# Generated by FakeRAM 2.0 (routing-friendly)
VERSION 5.7 ;
BUSBITCHARS "[]" ;
PROPERTYDEFINITIONS
  MACRO width INTEGER ;
  MACRO depth INTEGER ;
  MACRO banks INTEGER ;
END PROPERTYDEFINITIONS
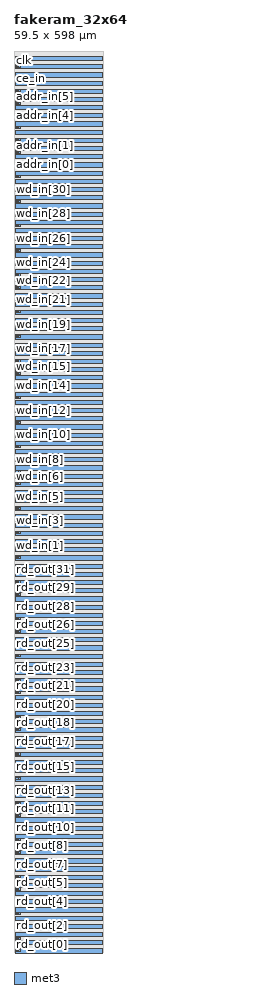
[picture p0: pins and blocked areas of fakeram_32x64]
MACRO fakeram_32x64
  PROPERTY width 32 ;
  PROPERTY depth 64 ;
  PROPERTY banks 1 ;
  FOREIGN fakeram_32x64 0 0 ;
  SYMMETRY X Y R90 ;
  SIZE 59.500 BY 598.000 ;
  CLASS BLOCK ;
  PIN rd_out[0]
    DIRECTION OUTPUT ;
    USE SIGNAL ;
    PORT
      LAYER met3 ;
      RECT 1.000 0.680 3.000 1.380 ;
    END
    PORT
      LAYER met3 ;
      RECT 1.000 0.330 4.000 1.730 ;
    END
  END rd_out[0]
  PIN rd_out[1]
    DIRECTION OUTPUT ;
    USE SIGNAL ;
    PORT
      LAYER met3 ;
      RECT 1.000 8.840 3.000 9.540 ;
    END
    PORT
      LAYER met3 ;
      RECT 1.000 8.490 4.000 9.890 ;
    END
  END rd_out[1]
  PIN rd_out[2]
    DIRECTION OUTPUT ;
    USE SIGNAL ;
    PORT
      LAYER met3 ;
      RECT 1.000 17.000 3.000 17.700 ;
    END
    PORT
      LAYER met3 ;
      RECT 1.000 16.650 4.000 18.050 ;
    END
  END rd_out[2]
  PIN rd_out[3]
    DIRECTION OUTPUT ;
    USE SIGNAL ;
    PORT
      LAYER met3 ;
      RECT 1.000 25.160 3.000 25.860 ;
    END
    PORT
      LAYER met3 ;
      RECT 1.000 24.810 4.000 26.210 ;
    END
  END rd_out[3]
  PIN rd_out[4]
    DIRECTION OUTPUT ;
    USE SIGNAL ;
    PORT
      LAYER met3 ;
      RECT 1.000 33.320 3.000 34.020 ;
    END
    PORT
      LAYER met3 ;
      RECT 1.000 32.970 4.000 34.370 ;
    END
  END rd_out[4]
  PIN rd_out[5]
    DIRECTION OUTPUT ;
    USE SIGNAL ;
    PORT
      LAYER met3 ;
      RECT 1.000 41.480 3.000 42.180 ;
    END
    PORT
      LAYER met3 ;
      RECT 1.000 41.130 4.000 42.530 ;
    END
  END rd_out[5]
  PIN rd_out[6]
    DIRECTION OUTPUT ;
    USE SIGNAL ;
    PORT
      LAYER met3 ;
      RECT 1.000 49.640 3.000 50.340 ;
    END
    PORT
      LAYER met3 ;
      RECT 1.000 49.290 4.000 50.690 ;
    END
  END rd_out[6]
  PIN rd_out[7]
    DIRECTION OUTPUT ;
    USE SIGNAL ;
    PORT
      LAYER met3 ;
      RECT 1.000 57.800 3.000 58.500 ;
    END
    PORT
      LAYER met3 ;
      RECT 1.000 57.450 4.000 58.850 ;
    END
  END rd_out[7]
  PIN rd_out[8]
    DIRECTION OUTPUT ;
    USE SIGNAL ;
    PORT
      LAYER met3 ;
      RECT 1.000 65.960 3.000 66.660 ;
    END
    PORT
      LAYER met3 ;
      RECT 1.000 65.610 4.000 67.010 ;
    END
  END rd_out[8]
  PIN rd_out[9]
    DIRECTION OUTPUT ;
    USE SIGNAL ;
    PORT
      LAYER met3 ;
      RECT 1.000 74.120 3.000 74.820 ;
    END
    PORT
      LAYER met3 ;
      RECT 1.000 73.770 4.000 75.170 ;
    END
  END rd_out[9]
  PIN rd_out[10]
    DIRECTION OUTPUT ;
    USE SIGNAL ;
    PORT
      LAYER met3 ;
      RECT 1.000 82.280 3.000 82.980 ;
    END
    PORT
      LAYER met3 ;
      RECT 1.000 81.930 4.000 83.330 ;
    END
  END rd_out[10]
  PIN rd_out[11]
    DIRECTION OUTPUT ;
    USE SIGNAL ;
    PORT
      LAYER met3 ;
      RECT 1.000 90.440 3.000 91.140 ;
    END
    PORT
      LAYER met3 ;
      RECT 1.000 90.090 4.000 91.490 ;
    END
  END rd_out[11]
  PIN rd_out[12]
    DIRECTION OUTPUT ;
    USE SIGNAL ;
    PORT
      LAYER met3 ;
      RECT 1.000 98.600 3.000 99.300 ;
    END
    PORT
      LAYER met3 ;
      RECT 1.000 98.250 4.000 99.650 ;
    END
  END rd_out[12]
  PIN rd_out[13]
    DIRECTION OUTPUT ;
    USE SIGNAL ;
    PORT
      LAYER met3 ;
      RECT 1.000 106.760 3.000 107.460 ;
    END
    PORT
      LAYER met3 ;
      RECT 1.000 106.410 4.000 107.810 ;
    END
  END rd_out[13]
  PIN rd_out[14]
    DIRECTION OUTPUT ;
    USE SIGNAL ;
    PORT
      LAYER met3 ;
      RECT 1.000 114.920 3.000 115.620 ;
    END
    PORT
      LAYER met3 ;
      RECT 1.000 114.570 4.000 115.970 ;
    END
  END rd_out[14]
  PIN rd_out[15]
    DIRECTION OUTPUT ;
    USE SIGNAL ;
    PORT
      LAYER met3 ;
      RECT 1.000 123.080 3.000 123.780 ;
    END
    PORT
      LAYER met3 ;
      RECT 1.000 122.730 4.000 124.130 ;
    END
  END rd_out[15]
  PIN rd_out[16]
    DIRECTION OUTPUT ;
    USE SIGNAL ;
    PORT
      LAYER met3 ;
      RECT 1.000 131.240 3.000 131.940 ;
    END
    PORT
      LAYER met3 ;
      RECT 1.000 130.890 4.000 132.290 ;
    END
  END rd_out[16]
  PIN rd_out[17]
    DIRECTION OUTPUT ;
    USE SIGNAL ;
    PORT
      LAYER met3 ;
      RECT 1.000 139.400 3.000 140.100 ;
    END
    PORT
      LAYER met3 ;
      RECT 1.000 139.050 4.000 140.450 ;
    END
  END rd_out[17]
  PIN rd_out[18]
    DIRECTION OUTPUT ;
    USE SIGNAL ;
    PORT
      LAYER met3 ;
      RECT 1.000 147.560 3.000 148.260 ;
    END
    PORT
      LAYER met3 ;
      RECT 1.000 147.210 4.000 148.610 ;
    END
  END rd_out[18]
  PIN rd_out[19]
    DIRECTION OUTPUT ;
    USE SIGNAL ;
    PORT
      LAYER met3 ;
      RECT 1.000 155.720 3.000 156.420 ;
    END
    PORT
      LAYER met3 ;
      RECT 1.000 155.370 4.000 156.770 ;
    END
  END rd_out[19]
  PIN rd_out[20]
    DIRECTION OUTPUT ;
    USE SIGNAL ;
    PORT
      LAYER met3 ;
      RECT 1.000 163.880 3.000 164.580 ;
    END
    PORT
      LAYER met3 ;
      RECT 1.000 163.530 4.000 164.930 ;
    END
  END rd_out[20]
  PIN rd_out[21]
    DIRECTION OUTPUT ;
    USE SIGNAL ;
    PORT
      LAYER met3 ;
      RECT 1.000 172.040 3.000 172.740 ;
    END
    PORT
      LAYER met3 ;
      RECT 1.000 171.690 4.000 173.090 ;
    END
  END rd_out[21]
  PIN rd_out[22]
    DIRECTION OUTPUT ;
    USE SIGNAL ;
    PORT
      LAYER met3 ;
      RECT 1.000 180.200 3.000 180.900 ;
    END
    PORT
      LAYER met3 ;
      RECT 1.000 179.850 4.000 181.250 ;
    END
  END rd_out[22]
  PIN rd_out[23]
    DIRECTION OUTPUT ;
    USE SIGNAL ;
    PORT
      LAYER met3 ;
      RECT 1.000 188.360 3.000 189.060 ;
    END
    PORT
      LAYER met3 ;
      RECT 1.000 188.010 4.000 189.410 ;
    END
  END rd_out[23]
  PIN rd_out[24]
    DIRECTION OUTPUT ;
    USE SIGNAL ;
    PORT
      LAYER met3 ;
      RECT 1.000 196.520 3.000 197.220 ;
    END
    PORT
      LAYER met3 ;
      RECT 1.000 196.170 4.000 197.570 ;
    END
  END rd_out[24]
  PIN rd_out[25]
    DIRECTION OUTPUT ;
    USE SIGNAL ;
    PORT
      LAYER met3 ;
      RECT 1.000 204.680 3.000 205.380 ;
    END
    PORT
      LAYER met3 ;
      RECT 1.000 204.330 4.000 205.730 ;
    END
  END rd_out[25]
  PIN rd_out[26]
    DIRECTION OUTPUT ;
    USE SIGNAL ;
    PORT
      LAYER met3 ;
      RECT 1.000 212.840 3.000 213.540 ;
    END
    PORT
      LAYER met3 ;
      RECT 1.000 212.490 4.000 213.890 ;
    END
  END rd_out[26]
  PIN rd_out[27]
    DIRECTION OUTPUT ;
    USE SIGNAL ;
    PORT
      LAYER met3 ;
      RECT 1.000 221.000 3.000 221.700 ;
    END
    PORT
      LAYER met3 ;
      RECT 1.000 220.650 4.000 222.050 ;
    END
  END rd_out[27]
  PIN rd_out[28]
    DIRECTION OUTPUT ;
    USE SIGNAL ;
    PORT
      LAYER met3 ;
      RECT 1.000 229.160 3.000 229.860 ;
    END
    PORT
      LAYER met3 ;
      RECT 1.000 228.810 4.000 230.210 ;
    END
  END rd_out[28]
  PIN rd_out[29]
    DIRECTION OUTPUT ;
    USE SIGNAL ;
    PORT
      LAYER met3 ;
      RECT 1.000 237.320 3.000 238.020 ;
    END
    PORT
      LAYER met3 ;
      RECT 1.000 236.970 4.000 238.370 ;
    END
  END rd_out[29]
  PIN rd_out[30]
    DIRECTION OUTPUT ;
    USE SIGNAL ;
    PORT
      LAYER met3 ;
      RECT 1.000 245.480 3.000 246.180 ;
    END
    PORT
      LAYER met3 ;
      RECT 1.000 245.130 4.000 246.530 ;
    END
  END rd_out[30]
  PIN rd_out[31]
    DIRECTION OUTPUT ;
    USE SIGNAL ;
    PORT
      LAYER met3 ;
      RECT 1.000 253.640 3.000 254.340 ;
    END
    PORT
      LAYER met3 ;
      RECT 1.000 253.290 4.000 254.690 ;
    END
  END rd_out[31]
  PIN wd_in[0]
    DIRECTION INPUT ;
    USE SIGNAL ;
    PORT
      LAYER met3 ;
      RECT 1.000 261.800 3.000 262.500 ;
    END
    PORT
      LAYER met3 ;
      RECT 1.000 261.450 4.000 262.850 ;
    END
  END wd_in[0]
  PIN wd_in[1]
    DIRECTION INPUT ;
    USE SIGNAL ;
    PORT
      LAYER met3 ;
      RECT 1.000 269.960 3.000 270.660 ;
    END
    PORT
      LAYER met3 ;
      RECT 1.000 269.610 4.000 271.010 ;
    END
  END wd_in[1]
  PIN wd_in[2]
    DIRECTION INPUT ;
    USE SIGNAL ;
    PORT
      LAYER met3 ;
      RECT 1.000 278.120 3.000 278.820 ;
    END
    PORT
      LAYER met3 ;
      RECT 1.000 277.770 4.000 279.170 ;
    END
  END wd_in[2]
  PIN wd_in[3]
    DIRECTION INPUT ;
    USE SIGNAL ;
    PORT
      LAYER met3 ;
      RECT 1.000 286.280 3.000 286.980 ;
    END
    PORT
      LAYER met3 ;
      RECT 1.000 285.930 4.000 287.330 ;
    END
  END wd_in[3]
  PIN wd_in[4]
    DIRECTION INPUT ;
    USE SIGNAL ;
    PORT
      LAYER met3 ;
      RECT 1.000 294.440 3.000 295.140 ;
    END
    PORT
      LAYER met3 ;
      RECT 1.000 294.090 4.000 295.490 ;
    END
  END wd_in[4]
  PIN wd_in[5]
    DIRECTION INPUT ;
    USE SIGNAL ;
    PORT
      LAYER met3 ;
      RECT 1.000 302.600 3.000 303.300 ;
    END
    PORT
      LAYER met3 ;
      RECT 1.000 302.250 4.000 303.650 ;
    END
  END wd_in[5]
  PIN wd_in[6]
    DIRECTION INPUT ;
    USE SIGNAL ;
    PORT
      LAYER met3 ;
      RECT 1.000 310.760 3.000 311.460 ;
    END
    PORT
      LAYER met3 ;
      RECT 1.000 310.410 4.000 311.810 ;
    END
  END wd_in[6]
  PIN wd_in[7]
    DIRECTION INPUT ;
    USE SIGNAL ;
    PORT
      LAYER met3 ;
      RECT 1.000 318.920 3.000 319.620 ;
    END
    PORT
      LAYER met3 ;
      RECT 1.000 318.570 4.000 319.970 ;
    END
  END wd_in[7]
  PIN wd_in[8]
    DIRECTION INPUT ;
    USE SIGNAL ;
    PORT
      LAYER met3 ;
      RECT 1.000 327.080 3.000 327.780 ;
    END
    PORT
      LAYER met3 ;
      RECT 1.000 326.730 4.000 328.130 ;
    END
  END wd_in[8]
  PIN wd_in[9]
    DIRECTION INPUT ;
    USE SIGNAL ;
    PORT
      LAYER met3 ;
      RECT 1.000 335.240 3.000 335.940 ;
    END
    PORT
      LAYER met3 ;
      RECT 1.000 334.890 4.000 336.290 ;
    END
  END wd_in[9]
  PIN wd_in[10]
    DIRECTION INPUT ;
    USE SIGNAL ;
    PORT
      LAYER met3 ;
      RECT 1.000 343.400 3.000 344.100 ;
    END
    PORT
      LAYER met3 ;
      RECT 1.000 343.050 4.000 344.450 ;
    END
  END wd_in[10]
  PIN wd_in[11]
    DIRECTION INPUT ;
    USE SIGNAL ;
    PORT
      LAYER met3 ;
      RECT 1.000 351.560 3.000 352.260 ;
    END
    PORT
      LAYER met3 ;
      RECT 1.000 351.210 4.000 352.610 ;
    END
  END wd_in[11]
  PIN wd_in[12]
    DIRECTION INPUT ;
    USE SIGNAL ;
    PORT
      LAYER met3 ;
      RECT 1.000 359.720 3.000 360.420 ;
    END
    PORT
      LAYER met3 ;
      RECT 1.000 359.370 4.000 360.770 ;
    END
  END wd_in[12]
  PIN wd_in[13]
    DIRECTION INPUT ;
    USE SIGNAL ;
    PORT
      LAYER met3 ;
      RECT 1.000 367.880 3.000 368.580 ;
    END
    PORT
      LAYER met3 ;
      RECT 1.000 367.530 4.000 368.930 ;
    END
  END wd_in[13]
  PIN wd_in[14]
    DIRECTION INPUT ;
    USE SIGNAL ;
    PORT
      LAYER met3 ;
      RECT 1.000 376.040 3.000 376.740 ;
    END
    PORT
      LAYER met3 ;
      RECT 1.000 375.690 4.000 377.090 ;
    END
  END wd_in[14]
  PIN wd_in[15]
    DIRECTION INPUT ;
    USE SIGNAL ;
    PORT
      LAYER met3 ;
      RECT 1.000 384.200 3.000 384.900 ;
    END
    PORT
      LAYER met3 ;
      RECT 1.000 383.850 4.000 385.250 ;
    END
  END wd_in[15]
  PIN wd_in[16]
    DIRECTION INPUT ;
    USE SIGNAL ;
    PORT
      LAYER met3 ;
      RECT 1.000 392.360 3.000 393.060 ;
    END
    PORT
      LAYER met3 ;
      RECT 1.000 392.010 4.000 393.410 ;
    END
  END wd_in[16]
  PIN wd_in[17]
    DIRECTION INPUT ;
    USE SIGNAL ;
    PORT
      LAYER met3 ;
      RECT 1.000 400.520 3.000 401.220 ;
    END
    PORT
      LAYER met3 ;
      RECT 1.000 400.170 4.000 401.570 ;
    END
  END wd_in[17]
  PIN wd_in[18]
    DIRECTION INPUT ;
    USE SIGNAL ;
    PORT
      LAYER met3 ;
      RECT 1.000 408.680 3.000 409.380 ;
    END
    PORT
      LAYER met3 ;
      RECT 1.000 408.330 4.000 409.730 ;
    END
  END wd_in[18]
  PIN wd_in[19]
    DIRECTION INPUT ;
    USE SIGNAL ;
    PORT
      LAYER met3 ;
      RECT 1.000 416.840 3.000 417.540 ;
    END
    PORT
      LAYER met3 ;
      RECT 1.000 416.490 4.000 417.890 ;
    END
  END wd_in[19]
  PIN wd_in[20]
    DIRECTION INPUT ;
    USE SIGNAL ;
    PORT
      LAYER met3 ;
      RECT 1.000 425.000 3.000 425.700 ;
    END
    PORT
      LAYER met3 ;
      RECT 1.000 424.650 4.000 426.050 ;
    END
  END wd_in[20]
  PIN wd_in[21]
    DIRECTION INPUT ;
    USE SIGNAL ;
    PORT
      LAYER met3 ;
      RECT 1.000 433.160 3.000 433.860 ;
    END
    PORT
      LAYER met3 ;
      RECT 1.000 432.810 4.000 434.210 ;
    END
  END wd_in[21]
  PIN wd_in[22]
    DIRECTION INPUT ;
    USE SIGNAL ;
    PORT
      LAYER met3 ;
      RECT 1.000 441.320 3.000 442.020 ;
    END
    PORT
      LAYER met3 ;
      RECT 1.000 440.970 4.000 442.370 ;
    END
  END wd_in[22]
  PIN wd_in[23]
    DIRECTION INPUT ;
    USE SIGNAL ;
    PORT
      LAYER met3 ;
      RECT 1.000 449.480 3.000 450.180 ;
    END
    PORT
      LAYER met3 ;
      RECT 1.000 449.130 4.000 450.530 ;
    END
  END wd_in[23]
  PIN wd_in[24]
    DIRECTION INPUT ;
    USE SIGNAL ;
    PORT
      LAYER met3 ;
      RECT 1.000 457.640 3.000 458.340 ;
    END
    PORT
      LAYER met3 ;
      RECT 1.000 457.290 4.000 458.690 ;
    END
  END wd_in[24]
  PIN wd_in[25]
    DIRECTION INPUT ;
    USE SIGNAL ;
    PORT
      LAYER met3 ;
      RECT 1.000 465.800 3.000 466.500 ;
    END
    PORT
      LAYER met3 ;
      RECT 1.000 465.450 4.000 466.850 ;
    END
  END wd_in[25]
  PIN wd_in[26]
    DIRECTION INPUT ;
    USE SIGNAL ;
    PORT
      LAYER met3 ;
      RECT 1.000 473.960 3.000 474.660 ;
    END
    PORT
      LAYER met3 ;
      RECT 1.000 473.610 4.000 475.010 ;
    END
  END wd_in[26]
  PIN wd_in[27]
    DIRECTION INPUT ;
    USE SIGNAL ;
    PORT
      LAYER met3 ;
      RECT 1.000 482.120 3.000 482.820 ;
    END
    PORT
      LAYER met3 ;
      RECT 1.000 481.770 4.000 483.170 ;
    END
  END wd_in[27]
  PIN wd_in[28]
    DIRECTION INPUT ;
    USE SIGNAL ;
    PORT
      LAYER met3 ;
      RECT 1.000 490.280 3.000 490.980 ;
    END
    PORT
      LAYER met3 ;
      RECT 1.000 489.930 4.000 491.330 ;
    END
  END wd_in[28]
  PIN wd_in[29]
    DIRECTION INPUT ;
    USE SIGNAL ;
    PORT
      LAYER met3 ;
      RECT 1.000 498.440 3.000 499.140 ;
    END
    PORT
      LAYER met3 ;
      RECT 1.000 498.090 4.000 499.490 ;
    END
  END wd_in[29]
  PIN wd_in[30]
    DIRECTION INPUT ;
    USE SIGNAL ;
    PORT
      LAYER met3 ;
      RECT 1.000 506.600 3.000 507.300 ;
    END
    PORT
      LAYER met3 ;
      RECT 1.000 506.250 4.000 507.650 ;
    END
  END wd_in[30]
  PIN wd_in[31]
    DIRECTION INPUT ;
    USE SIGNAL ;
    PORT
      LAYER met3 ;
      RECT 1.000 514.760 3.000 515.460 ;
    END
    PORT
      LAYER met3 ;
      RECT 1.000 514.410 4.000 515.810 ;
    END
  END wd_in[31]
  PIN addr_in[0]
    DIRECTION INPUT ;
    USE SIGNAL ;
    PORT
      LAYER met3 ;
      RECT 1.000 522.920 3.000 523.620 ;
    END
    PORT
      LAYER met3 ;
      RECT 1.000 522.570 4.000 523.970 ;
    END
  END addr_in[0]
  PIN addr_in[1]
    DIRECTION INPUT ;
    USE SIGNAL ;
    PORT
      LAYER met3 ;
      RECT 1.000 531.080 3.000 531.780 ;
    END
    PORT
      LAYER met3 ;
      RECT 1.000 530.730 4.000 532.130 ;
    END
  END addr_in[1]
  PIN addr_in[2]
    DIRECTION INPUT ;
    USE SIGNAL ;
    PORT
      LAYER met3 ;
      RECT 1.000 539.240 3.000 539.940 ;
    END
    PORT
      LAYER met3 ;
      RECT 1.000 538.890 4.000 540.290 ;
    END
  END addr_in[2]
  PIN addr_in[3]
    DIRECTION INPUT ;
    USE SIGNAL ;
    PORT
      LAYER met3 ;
      RECT 1.000 547.400 3.000 548.100 ;
    END
    PORT
      LAYER met3 ;
      RECT 1.000 547.050 4.000 548.450 ;
    END
  END addr_in[3]
  PIN addr_in[4]
    DIRECTION INPUT ;
    USE SIGNAL ;
    PORT
      LAYER met3 ;
      RECT 1.000 555.560 3.000 556.260 ;
    END
    PORT
      LAYER met3 ;
      RECT 1.000 555.210 4.000 556.610 ;
    END
  END addr_in[4]
  PIN addr_in[5]
    DIRECTION INPUT ;
    USE SIGNAL ;
    PORT
      LAYER met3 ;
      RECT 1.000 563.720 3.000 564.420 ;
    END
    PORT
      LAYER met3 ;
      RECT 1.000 563.370 4.000 564.770 ;
    END
  END addr_in[5]
  PIN we_in
    DIRECTION INPUT ;
    USE SIGNAL ;
    PORT
      LAYER met3 ;
      RECT 1.000 571.880 3.000 572.580 ;
    END
    PORT
      LAYER met3 ;
      RECT 1.000 571.530 4.000 572.930 ;
    END
  END we_in
  PIN ce_in
    DIRECTION INPUT ;
    USE SIGNAL ;
    PORT
      LAYER met3 ;
      RECT 1.000 580.040 3.000 580.740 ;
    END
    PORT
      LAYER met3 ;
      RECT 1.000 579.690 4.000 581.090 ;
    END
  END ce_in
  PIN clk
    DIRECTION INPUT ;
    USE SIGNAL ;
    PORT
      LAYER met3 ;
      RECT 1.000 588.200 3.000 588.900 ;
    END
    PORT
      LAYER met3 ;
      RECT 1.000 587.850 4.000 589.250 ;
    END
  END clk
  PIN VSS
    DIRECTION INOUT ;
    USE GROUND ;
    PORT
      LAYER met3 ;
      RECT 0.680 -0.720 58.820 2.080 ;
      RECT 0.680 10.160 58.820 12.960 ;
      RECT 0.680 21.040 58.820 23.840 ;
      RECT 0.680 31.920 58.820 34.720 ;
      RECT 0.680 42.800 58.820 45.600 ;
      RECT 0.680 53.680 58.820 56.480 ;
      RECT 0.680 64.560 58.820 67.360 ;
      RECT 0.680 75.440 58.820 78.240 ;
      RECT 0.680 86.320 58.820 89.120 ;
      RECT 0.680 97.200 58.820 100.000 ;
      RECT 0.680 108.080 58.820 110.880 ;
      RECT 0.680 118.960 58.820 121.760 ;
      RECT 0.680 129.840 58.820 132.640 ;
      RECT 0.680 140.720 58.820 143.520 ;
      RECT 0.680 151.600 58.820 154.400 ;
      RECT 0.680 162.480 58.820 165.280 ;
      RECT 0.680 173.360 58.820 176.160 ;
      RECT 0.680 184.240 58.820 187.040 ;
      RECT 0.680 195.120 58.820 197.920 ;
      RECT 0.680 206.000 58.820 208.800 ;
      RECT 0.680 216.880 58.820 219.680 ;
      RECT 0.680 227.760 58.820 230.560 ;
      RECT 0.680 238.640 58.820 241.440 ;
      RECT 0.680 249.520 58.820 252.320 ;
      RECT 0.680 260.400 58.820 263.200 ;
      RECT 0.680 271.280 58.820 274.080 ;
      RECT 0.680 282.160 58.820 284.960 ;
      RECT 0.680 293.040 58.820 295.840 ;
      RECT 0.680 303.920 58.820 306.720 ;
      RECT 0.680 314.800 58.820 317.600 ;
      RECT 0.680 325.680 58.820 328.480 ;
      RECT 0.680 336.560 58.820 339.360 ;
      RECT 0.680 347.440 58.820 350.240 ;
      RECT 0.680 358.320 58.820 361.120 ;
      RECT 0.680 369.200 58.820 372.000 ;
      RECT 0.680 380.080 58.820 382.880 ;
      RECT 0.680 390.960 58.820 393.760 ;
      RECT 0.680 401.840 58.820 404.640 ;
      RECT 0.680 412.720 58.820 415.520 ;
      RECT 0.680 423.600 58.820 426.400 ;
      RECT 0.680 434.480 58.820 437.280 ;
      RECT 0.680 445.360 58.820 448.160 ;
      RECT 0.680 456.240 58.820 459.040 ;
      RECT 0.680 467.120 58.820 469.920 ;
      RECT 0.680 478.000 58.820 480.800 ;
      RECT 0.680 488.880 58.820 491.680 ;
      RECT 0.680 499.760 58.820 502.560 ;
      RECT 0.680 510.640 58.820 513.440 ;
      RECT 0.680 521.520 58.820 524.320 ;
      RECT 0.680 532.400 58.820 535.200 ;
      RECT 0.680 543.280 58.820 546.080 ;
      RECT 0.680 554.160 58.820 556.960 ;
      RECT 0.680 565.040 58.820 567.840 ;
      RECT 0.680 575.920 58.820 578.720 ;
      RECT 0.680 586.800 58.820 589.600 ;
    END
  END VSS
  PIN VDD
    DIRECTION INOUT ;
    USE POWER ;
    PORT
      LAYER met3 ;
      RECT 0.680 4.720 58.820 7.520 ;
      RECT 0.680 15.600 58.820 18.400 ;
      RECT 0.680 26.480 58.820 29.280 ;
      RECT 0.680 37.360 58.820 40.160 ;
      RECT 0.680 48.240 58.820 51.040 ;
      RECT 0.680 59.120 58.820 61.920 ;
      RECT 0.680 70.000 58.820 72.800 ;
      RECT 0.680 80.880 58.820 83.680 ;
      RECT 0.680 91.760 58.820 94.560 ;
      RECT 0.680 102.640 58.820 105.440 ;
      RECT 0.680 113.520 58.820 116.320 ;
      RECT 0.680 124.400 58.820 127.200 ;
      RECT 0.680 135.280 58.820 138.080 ;
      RECT 0.680 146.160 58.820 148.960 ;
      RECT 0.680 157.040 58.820 159.840 ;
      RECT 0.680 167.920 58.820 170.720 ;
      RECT 0.680 178.800 58.820 181.600 ;
      RECT 0.680 189.680 58.820 192.480 ;
      RECT 0.680 200.560 58.820 203.360 ;
      RECT 0.680 211.440 58.820 214.240 ;
      RECT 0.680 222.320 58.820 225.120 ;
      RECT 0.680 233.200 58.820 236.000 ;
      RECT 0.680 244.080 58.820 246.880 ;
      RECT 0.680 254.960 58.820 257.760 ;
      RECT 0.680 265.840 58.820 268.640 ;
      RECT 0.680 276.720 58.820 279.520 ;
      RECT 0.680 287.600 58.820 290.400 ;
      RECT 0.680 298.480 58.820 301.280 ;
      RECT 0.680 309.360 58.820 312.160 ;
      RECT 0.680 320.240 58.820 323.040 ;
      RECT 0.680 331.120 58.820 333.920 ;
      RECT 0.680 342.000 58.820 344.800 ;
      RECT 0.680 352.880 58.820 355.680 ;
      RECT 0.680 363.760 58.820 366.560 ;
      RECT 0.680 374.640 58.820 377.440 ;
      RECT 0.680 385.520 58.820 388.320 ;
      RECT 0.680 396.400 58.820 399.200 ;
      RECT 0.680 407.280 58.820 410.080 ;
      RECT 0.680 418.160 58.820 420.960 ;
      RECT 0.680 429.040 58.820 431.840 ;
      RECT 0.680 439.920 58.820 442.720 ;
      RECT 0.680 450.800 58.820 453.600 ;
      RECT 0.680 461.680 58.820 464.480 ;
      RECT 0.680 472.560 58.820 475.360 ;
      RECT 0.680 483.440 58.820 486.240 ;
      RECT 0.680 494.320 58.820 497.120 ;
      RECT 0.680 505.200 58.820 508.000 ;
      RECT 0.680 516.080 58.820 518.880 ;
      RECT 0.680 526.960 58.820 529.760 ;
      RECT 0.680 537.840 58.820 540.640 ;
      RECT 0.680 548.720 58.820 551.520 ;
      RECT 0.680 559.600 58.820 562.400 ;
      RECT 0.680 570.480 58.820 573.280 ;
      RECT 0.680 581.360 58.820 584.160 ;
      RECT 0.680 592.240 58.820 595.040 ;
    END
  END VDD
  OBS
    LAYER met1 ;
    RECT 0 0 59.500 598.000 ;
    LAYER met2 ;
    RECT 0 0 59.500 598.000 ;
  END
END fakeram_32x64
END LIBRARY
